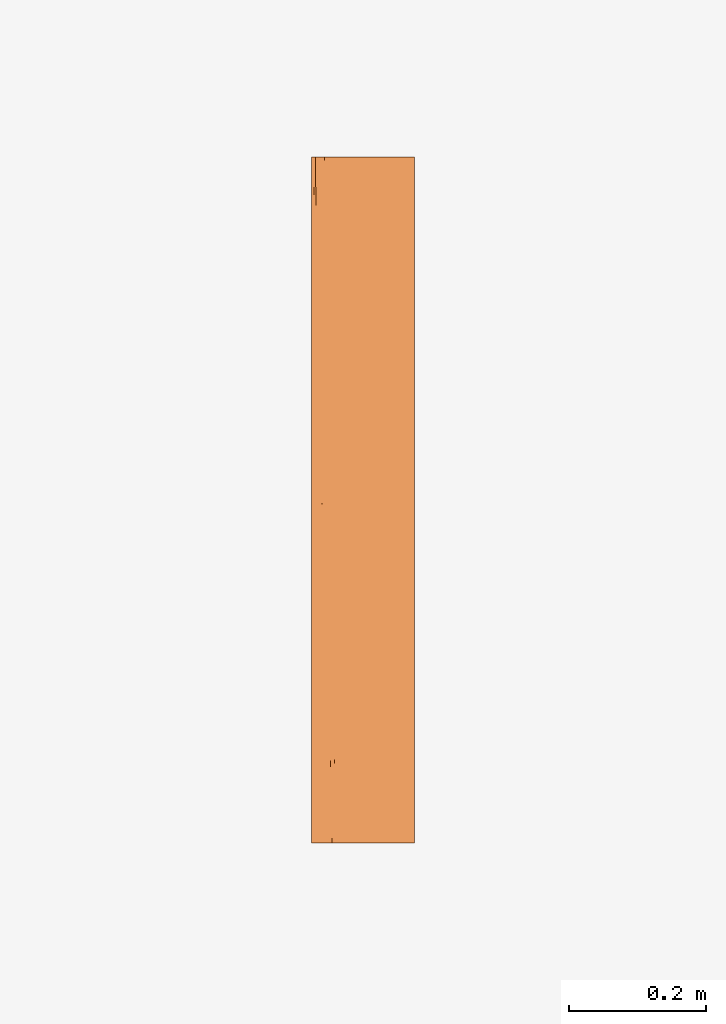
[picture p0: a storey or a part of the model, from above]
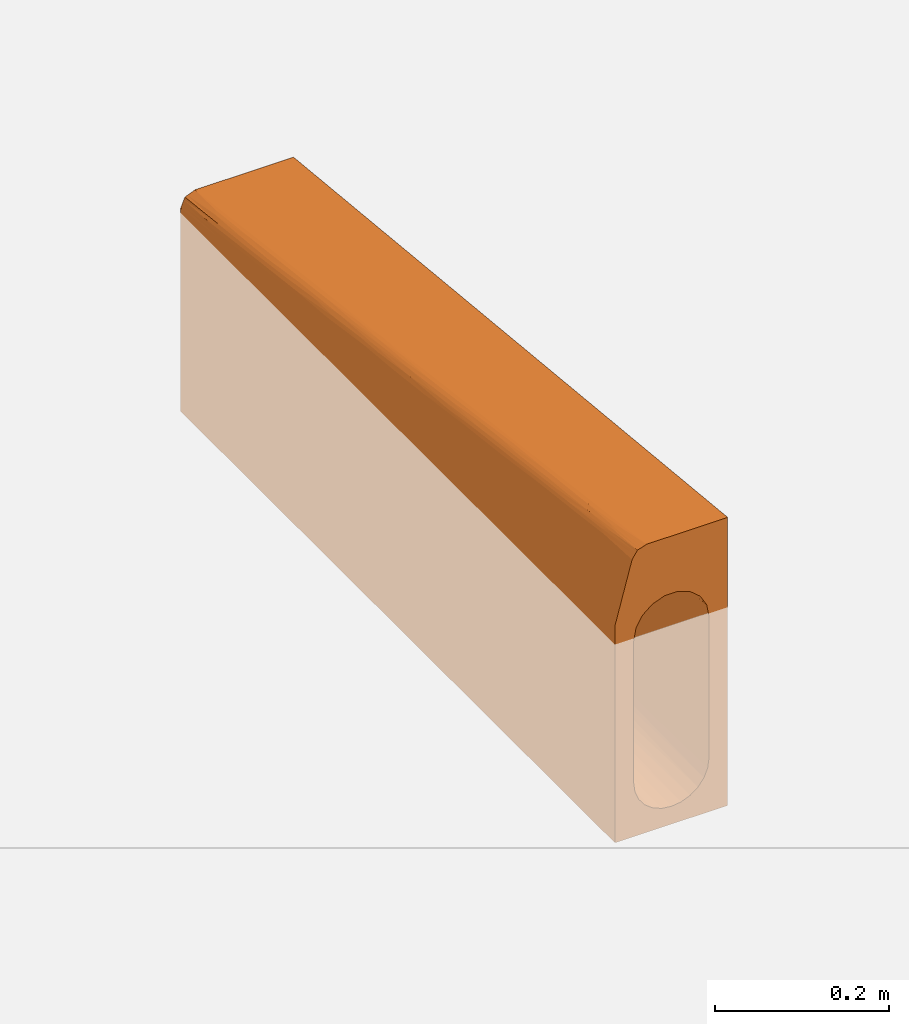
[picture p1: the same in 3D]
Properties of the parts of a building model (IFC2X3)

# File
Description: ViewDefinition [CoordinationView]
File name: 4235 - RH drop kerb - 1000mm LG.ifc
Time: 2013-09-02T12:42:01
Written by: Autodesk Revit 2013
Made in: 20120221_2030(x64)

# IfcProject, Project Number
LongName: Project Name; Phase: Project Status

# IfcSite, Default
RefLatitude: 42, 21, 30, 344238; RefLongitude: -71, -3, -35, -194702; RefElevation: 0 mm

# IfcBuilding
Pset_BuildingCommon - NumberOfStoreys: 1
Other - Project Status: Project Status; Client Name: Owner; Project Issue Date: Issue Date; Project Name: Project Name; Project Number: Project Number; Project Address: ## Street City, State Zip

# IfcBuildingStorey, Level 1
LongName: Level 1; Elevation: 0 mm
Constraints - Elevation Base: 0; Elevation: 0 mm
Graphics - Line Pattern: Center; Symbol at End 1 Default: no; Line Weight: 1; Symbol at End 2 Default: yes; Symbol: M_Level Head - Circle: M_Level Head - Circle; Color: 0
Dimensions - Computation Height: 0 mm
Identity Data - Name: Level 1; Structural: no; Building Story: yes

# IfcBuildingElementProxy: 4235 - RH drop kerb - 1000mm LG, Civil-Drainage-Channel-ACO-KerbDrain-HB405:4235 - RH drop kerb - 1000mm LG:4235 - RH drop kerb - 1000mm LG:312781
In: Level 1
Material: ACO Polymer Concrete.
Constraints - Moves With Nearby Elements: no; Level: Level: Level 1
Dimensions - Volume: 29809906 mm3; Circular Void Depth: 2000 mm; Void Length: 1000 mm; Void Depth: -280 mm; Void Width: 150 mm
Phasing - Phase Created: New Construction
Pset_BuildingElementProxyCommon - Reference: 4235 - RH drop kerb - 1000mm LG
Data - Concrete Surround Volume - Load Class A 15 - D 400 - Grass or Asphalt Pavement: N/A; Invert Depth: 380/280mm; Drainage Slot Intake area: N/A; Product Weight: 62.1 Kg; Connection Pipe O.D: N/A; Hydraulic Performance: http://www.aco.co.uk/download.php?id=120; Channel C.S.A: 0.03 to 0.02mm²; Load Class: A 15 - D 400; Installation - Concrete Grade: Refer to brochure; ACO Hydraulic Design Software: http://www.acodesign.co.uk; Product Standard: BS EN 1433:2002, CE marked, Kitemarked; Concrete Surround Volume - Load Class A 15 - D 400 - Concrete Pavement: N/A; Drainage Slot Width: N/A; Product Dimensions: 1000mm x 150mm x 405/305mm (LxWxH)
Identity Data - Cost: 0; Installation guidelines: http://www.aco.co.uk/download.php?id=120; e-mail Sales: customersupport@aco.co.uk; URL: www.aco.co.uk; Price: POA - contact ACO; Manufacturer: ACO Technologies plc - ACO Water Management Division; Address: ACO Business Park, Hitchin Road, Shefford, Bedfordshire, United Kingdom SG17 5TE; Assembly Description: Rain Water Drainage; OmniClass Number: 23.70.50.24; Model Description: Combined kerb and drainage system; Type Comments: ACO KerbDrain HB405 half battered right-hand drop kerb unit 1000mm long; Product Page URL: http://www.aco.co.uk/product_detail.php?id=3; OmniClass Title: Rainwater Removal; Maintenance guidelines: http://www.aco.co.uk/download.php?id=120; Product Code: 4235; Product brochure: http://www.aco.co.uk/download.php?id=120; Fax: +44 (0)1462 815895; Model: ACO KerbDrain HB405; e-mail Technical: technical@aco.co.uk; Assembly Code: D2040; Telephone: +44 (0)1462 816666
Construction - LH inlet/outlet end cap: no; HB405 500_blindunit: no; RH drop kerb: yes; Access Unit: no; RH inlet/outlet end cap: no; LH drop kerb: no; HB405 - 500: no; Closing end cap: no; Centre Stone: no; HB405 - 1000: no
Green Building Properties - End Cap Recyclable: N/A; Access Cover/Frame Recyclable: N/A; End Cap Recycled Material Content: N/A; Access Cover/Frame Recycled Material Content: N/A; Channel Recyclable: Fully recyclable; Channel Recycled Material Content: 20% minimum
Materials and Finishes - Access Cover/Frame Finish: N/A; Channel Material: Vienite® Synthetic Resin Concrete; Channel Colour: Grey; Connection Pipe Material: N/A; Access Cover/Frame Material: N/A; End Cap Colour: N/A; End Cap Material: N/A; Connection Pipe Material Colour: N/A; Access Cover/Frame Colour: N/A
General - TagNumber: 0.000000; SerialNumber: 0.000000
Other - CreatedBy: www.aco.co.uk; Revision: 1

# IfcOpeningElement: Recess (2)
In: Level 1
Dimensions - Volume: 60546000000 mm3; Thickness: 400 mm; Area: 151470000 mm2; Perimeter: 51360 mm
Constraints - Height Offset From Level: 0 mm; Related to Mass: no; Room Bounding: yes; Level: Level: Level 1
Structural - Enable Analytical Model: no; Structural: no
Phasing - Phase Created: New Construction
Construction - Default Thickness: 400 mm; Function: 0
Graphics - Coarse Scale Fill Color: 0
Analytical Properties - Absorptance: 0.1; Roughness: 1
Materials and Finishes - Structural Material: Plant

# IfcSlab: Floor:Generic Floor - 400mm, Floor:Generic Floor - 400mm:193825
In: Level 1
PredefinedType: FLOOR; Material: Plant 400 mm
Dimensions - Volume: 60546000000 mm3; Thickness: 400 mm; Area: 151470000 mm2; Perimeter: 51360 mm
Constraints - Height Offset From Level: 0 mm; Related to Mass: no; Room Bounding: yes; Level: Level: Level 1
Structural - Enable Analytical Model: no; Structural: no
Phasing - Phase Created: New Construction
Pset_SlabCommon - Reference: Generic Floor - 400mm; IsExternal: no; LoadBearing: yes
Construction - Default Thickness: 400 mm; Function: 0
Graphics - Coarse Scale Fill Color: 0
Analytical Properties - Absorptance: 0.1; Roughness: 1
Materials and Finishes - Structural Material: Plant
